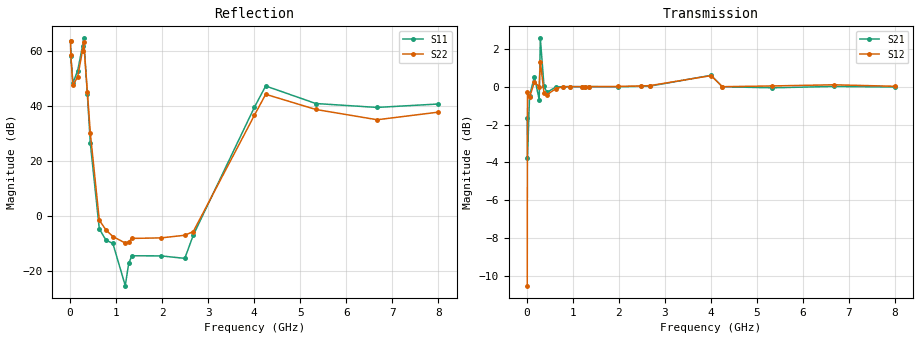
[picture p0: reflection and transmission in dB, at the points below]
!Agilent Technologies,N5230A,US43500312,A.07.50.67
!Agilent N5230A: A.07.50.67
!Date: Tuesday, June 09, 2015 15:34:02
!Correction: S11(Full 2 Port(1,2))
!S21(Full 2 Port(1,2))
!S12(Full 2 Port(1,2))
!S22(Full 2 Port(1,2))
!S2P File: Measurements: S11, S21, S12, S22:
# Hz S  MA  R 50
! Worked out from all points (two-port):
!   1601 points, 10 MHz to 8 GHz, reference 50 ohm
!   highest |S21| = 2.54 dB at 294.6 MHz (marker M1); lowest = -3.8 dB at 14.99 MHz (marker M2)
!   |S21| within 3 dB of the highest: 95.43 MHz to 139.6 MHz (44.2 MHz wide, 37.6 % of centre); 381.5 MHz to end of sweep (the widest 2 of 16)
!   lowest |S11| = -25.5 dB at 1.199 GHz (marker M3), VSWR 1.11, Z = 54.6 + j3.06 ohm
!   |S11| at or under -10 dB: 789.1 MHz to 932.3 MHz (143.2 MHz wide, 16.6 % of centre); 1.046 GHz to 2.087 GHz (1.042 GHz wide, 66.5 % of centre); 2.369 GHz to 2.617 GHz (248.6 MHz wide, 9.97 % of centre) (the widest 3 of 4)
!   |S22| runs from -13.9 to 63.6 dB; largest |S21 - S12| = 0.67
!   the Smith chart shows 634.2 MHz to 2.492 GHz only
!   S11 on the Smith chart (normalised r, x): 634.2 MHz: 0.39, +0.62; 779 MHz: 0.49, +0.17; 928.9 MHz: 0.91, -0.62; 1.273 GHz: 0.91, +0.24; 1.978 GHz: 0.70, +0.11; 2.492 GHz: 0.73, -0.11
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1e7  1499 171.1  0.8276 -42.6  0.2988 6.7  1521 -19.5
1.499375e7  814.4 226.2  0.6471 15.5  0.9649 -7.8  828.1 32.4
5.99375e7  257.7 325.8  0.943 -2.1  0.9376 3.6  233.1 92.2
1.648062e8  434.3 400.8  1.063 3.7  1.027 2.4  338.2 123.0
2.69675e8  1223 382.3  0.9239 -5.0  1 -13.1  1004 100.0
2.946438e8  1677 408.6  1.34 14.8  1.164 -3.0  1443 129.4
3.745438e8  160.9 432.2  1.002 1.8  0.9624 0.5  179.5 175.1
4.394625e8  20.52 411.4  0.9657 1.1  0.9516 1.1  31.49 194.7
6.342188e8  0.5734 470.9  0.9977 2.0  0.9883 2.1  0.8243 373.2
7.790375e8  0.3573 515.2  0.9991 1.6  0.9985 1.4  0.548 452.8
9.2885e8  0.311 639.9  1 1.5  1 1.6  0.4155 576.8
1.198512e9  0.053 751.8  0.9998 1.7  0.9994 1.8  0.3169 686.1
1.273419e9  0.1357 823.3  1 1.6  0.9998 1.7  0.3317 733.2
1.343331e9  0.1858 837.0  1 1.6  1 1.7  0.3841 762.8
1.977538e9  0.1847 875.4  0.9986 1.5  1.001 1.5  0.3928 1028.5
2.491894e9  0.1664 925.0  1.002 1.7  1.004 1.7  0.4384 1150.6
2.676662e9  0.442 1015.6  1.003 1.7  1.006 1.8  0.5122 1231.1
4.005e9  93.71 1391.3  1.071 -0.1  1.069 -0.5  66.95 1520.3
4.249694e9  228 1341.7  0.999 -2.1  0.9994 -0.9  161 1460.0
5.338331e9  109.4 1319.2  0.9928 0.5  1.004 0.4  85.27 1399.5
6.671662e9  92.83 1357.2  1.001 -0.2  1.011 0.3  55.42 1338.7
8e9  107.2 1385.9  0.9974 0.6  1.002 1.1  76.21 1307.1
